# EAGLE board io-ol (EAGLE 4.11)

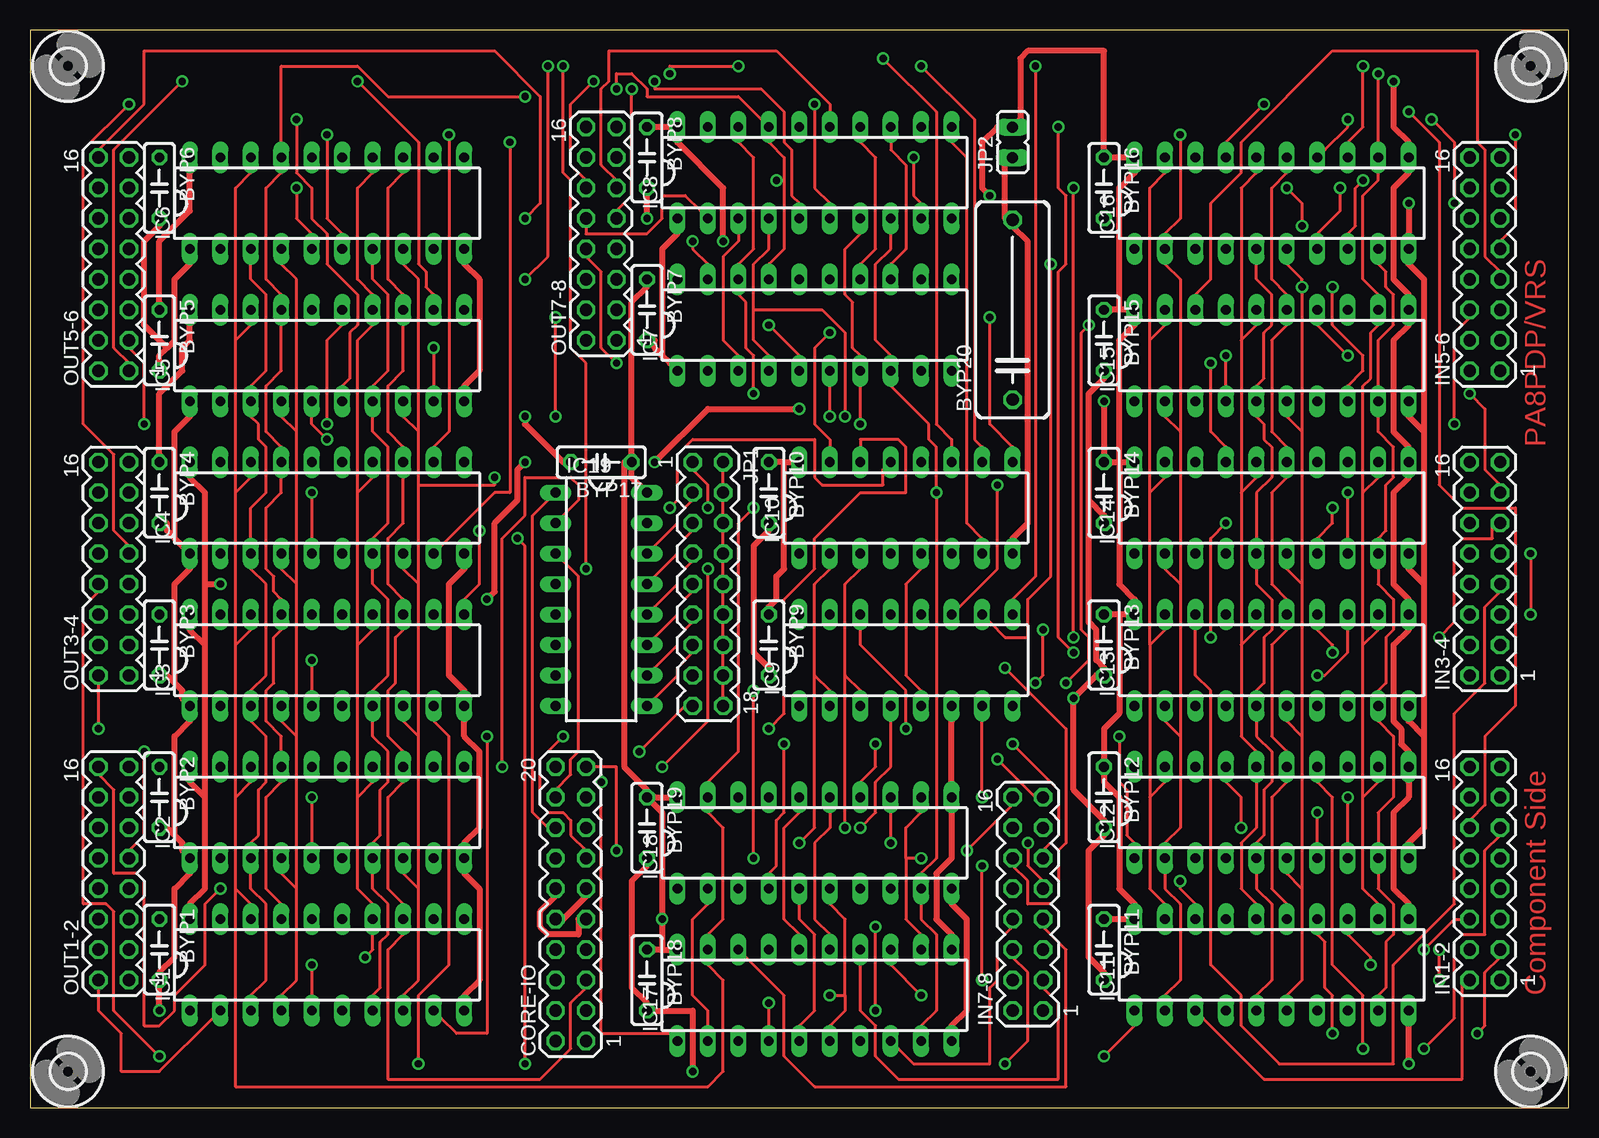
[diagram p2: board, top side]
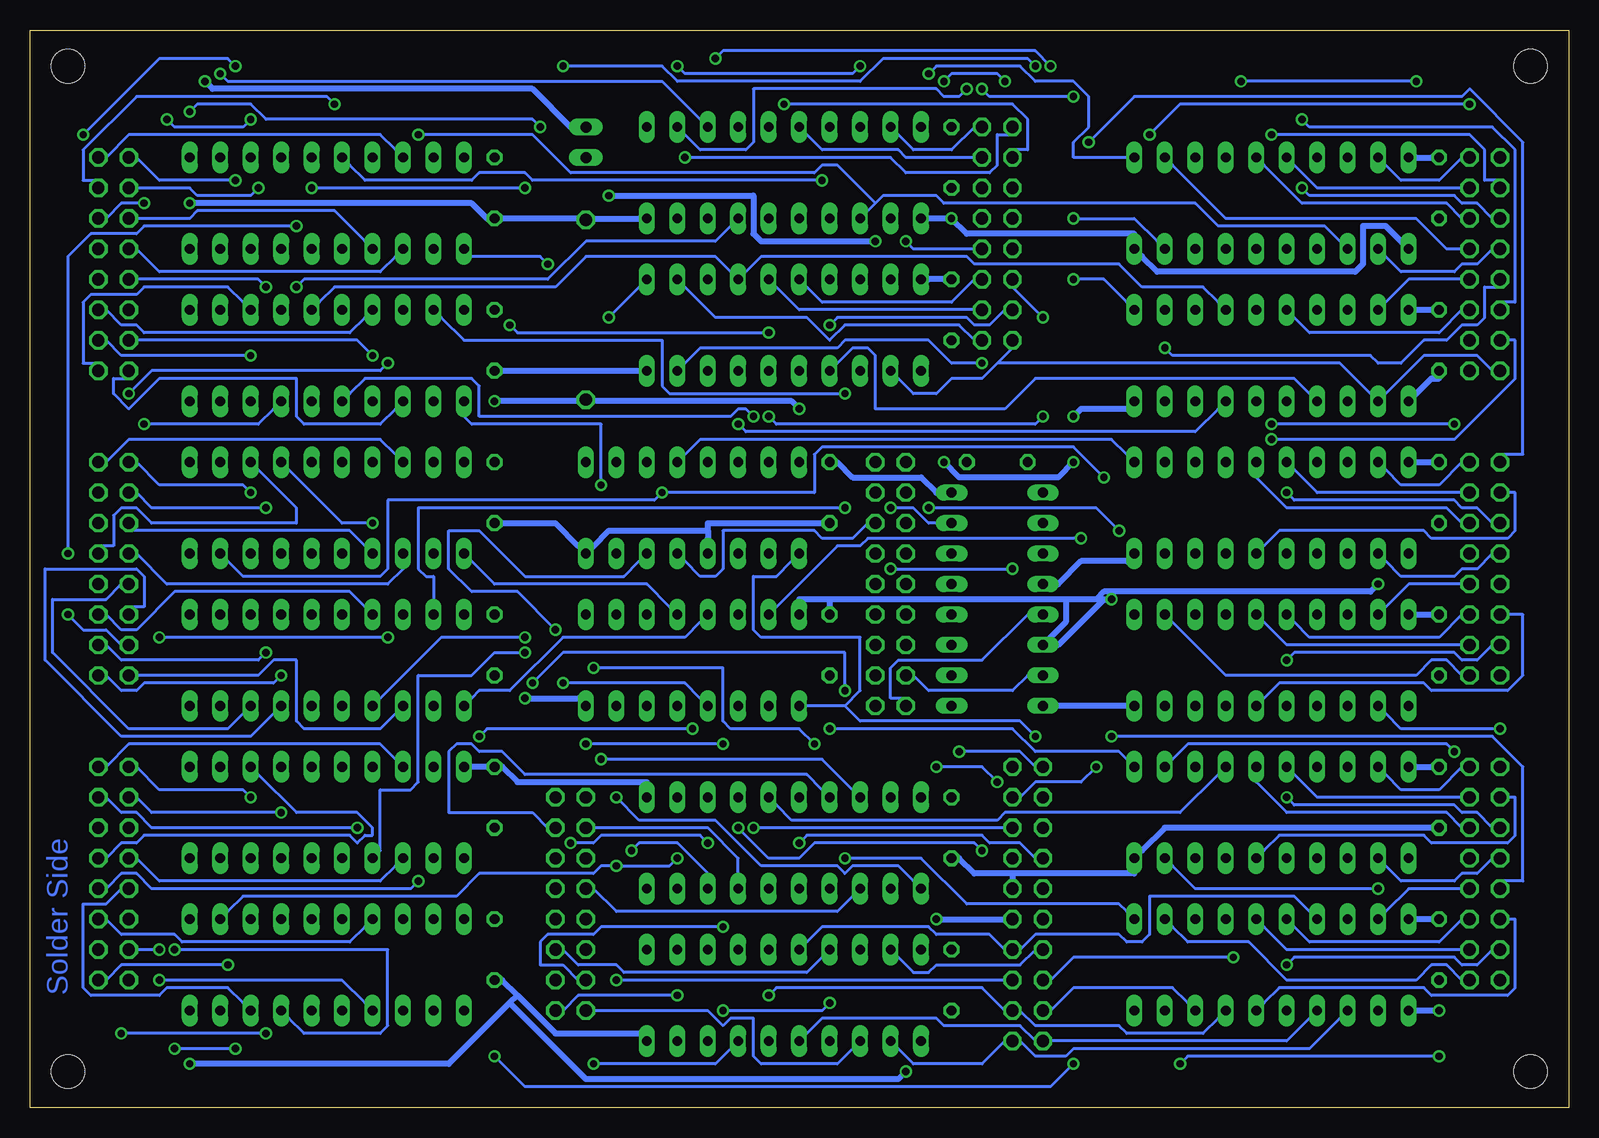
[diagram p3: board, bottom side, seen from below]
Size 128.25 x 89.84 mm. Coordinates in mm from the lower left corner, seen from the top.
Outline: 0,0 128.25,0 128.25,89.84 0,89.84 0,0
Copper layers (1*16): Top 0.035mm / dielectric 1.5mm / Bottom 0.035mm
Design rules "olimex10mil": minimum track width 10mil, minimum drill 24mil, track to track 10mil, track to pad 10mil, pad to pad 10mil, via to via 10mil, smd to smd 10mil, copper to edge 40mil, drill to drill 10mil, minimum pad ring 10mil, minimum via ring 8mil, stop-mask expansion 0mil, vias tented up to drill 0mil, thermal gap 10mil
Net classes: 1 Power: width 0.508 mm, drill 0.254 mm, clearance 0.254 mm

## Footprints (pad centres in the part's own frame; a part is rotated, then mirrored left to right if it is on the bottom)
C050-025X075 = drill 0.813 octagon: 1 -2.54,0; 2 2.54,0
C150-064X183 = drill 1.016 octagon: 1 -7.493,0; 2 7.493,0
MA10-2 = drill 1.016 octagon: 1 -11.43,-1.27; 2 -11.43,1.27; 3 -8.89,-1.27; 4 -8.89,1.27; 5 -6.35,-1.27; 6 -6.35,1.27; 7 -3.81,-1.27; 8 -3.81,1.27; 9 -1.27,-1.27; 10 -1.27,1.27; 11 1.27,-1.27; 12 1.27,1.27; 13 3.81,-1.27; 14 3.81,1.27; 15 6.35,-1.27; 16 6.35,1.27; 17 8.89,-1.27; 18 8.89,1.27; 19 11.43,-1.27; 20 11.43,1.27
DIL20 = drill 0.813 long: 1 -11.43,-3.81; 2 -8.89,-3.81; 3 -6.35,-3.81; 4 -3.81,-3.81; 5 -1.27,-3.81; 6 1.27,-3.81; 7 3.81,-3.81; 8 6.35,-3.81; 9 8.89,-3.81; 10 11.43,-3.81; 11 11.43,3.81; 12 8.89,3.81; 13 6.35,3.81; 14 3.81,3.81; 15 1.27,3.81; 16 -1.27,3.81; 17 -3.81,3.81; 18 -6.35,3.81; 19 -8.89,3.81; 20 -11.43,3.81
DIL16 = drill 0.813 long: 1 -8.89,-3.81; 2 -6.35,-3.81; 3 -3.81,-3.81; 4 -1.27,-3.81; 5 1.27,-3.81; 6 3.81,-3.81; 7 6.35,-3.81; 8 8.89,-3.81; 9 8.89,3.81; 10 6.35,3.81; 11 3.81,3.81; 12 1.27,3.81; 13 -1.27,3.81; 14 -3.81,3.81; 15 -6.35,3.81; 16 -8.89,3.81
MA08-2 = drill 1.016 octagon: 1 -8.89,-1.27; 2 -8.89,1.27; 3 -6.35,-1.27; 4 -6.35,1.27; 5 -3.81,-1.27; 6 -3.81,1.27; 7 -1.27,-1.27; 8 -1.27,1.27; 9 1.27,-1.27; 10 1.27,1.27; 11 3.81,-1.27; 12 3.81,1.27; 13 6.35,-1.27; 14 6.35,1.27; 15 8.89,-1.27; 16 8.89,1.27
MA09-2 = drill 1.016 octagon: 1 -10.16,-1.27; 2 -10.16,1.27; 3 -7.62,-1.27; 4 -7.62,1.27; 5 -5.08,-1.27; 6 -5.08,1.27; 7 -2.54,-1.27; 8 -2.54,1.27; 9 0,-1.27; 10 0,1.27; 11 2.54,-1.27; 12 2.54,1.27; 13 5.08,-1.27; 14 5.08,1.27; 15 7.62,-1.27; 16 7.62,1.27; 17 10.16,-1.27; 18 10.16,1.27
JP1 = drill 0.914 long: 1 0,-1.27; 2 0,1.27
2,8 = hole 2.8: 0,0

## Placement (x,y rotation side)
BYP1  .01uf  [C050-025X075]  10.79,13.17 270 top
BYP2  .01uf  [C050-025X075]  10.79,25.87 270 top
BYP3  .01uf  [C050-025X075]  10.79,38.57 270 top
BYP4  .01uf  [C050-025X075]  10.79,51.27 270 top
BYP5  .01uf  [C050-025X075]  10.79,63.97 270 top
BYP6  .01uf  [C050-025X075]  10.79,76.67 270 top
BYP7  .01uf  [C050-025X075]  51.43,66.51 270 top
BYP8  .01uf  [C050-025X075]  51.43,79.21 270 top
BYP9  .01uf  [C050-025X075]  61.59,38.57 270 top
BYP10  .01uf  [C050-025X075]  61.59,51.27 270 top
BYP11  .01uf  [C050-025X075]  89.53,13.17 270 top
BYP12  .01uf  [C050-025X075]  89.53,25.87 270 top
BYP13  .01uf  [C050-025X075]  89.53,38.57 270 top
BYP14  .01uf  [C050-025X075]  89.53,51.27 270 top
BYP15  .01uf  [C050-025X075]  89.53,63.97 270 top
BYP16  .01uf  [C050-025X075]  89.53,76.67 270 top
BYP17  .01uf  [C050-025X075]  47.62,53.81 180 top
BYP18  .01uf  [C050-025X075]  51.43,10.63 270 top
BYP19  .01uf  [C050-025X075]  51.43,23.33 270 top
BYP20  100uf 25V  [C150-064X183]  81.91,66.51 90 top
CORE-IO  CORE-IO  [MA10-2]  45.08,16.98 90 top
IC1  74LS374N  [DIL20]  24.76,11.9 0 top
IC2  74LS374N  [DIL20]  24.76,24.6 0 top
IC3  74LS374N  [DIL20]  24.76,37.3 0 top
IC4  74LS374N  [DIL20]  24.76,50 0 top
IC5  74LS374N  [DIL20]  24.76,62.7 0 top
IC6  74LS374N  [DIL20]  24.76,75.4 0 top
IC7  74LS374N  [DIL20]  65.4,65.24 0 top
IC8  74LS374N  [DIL20]  65.4,77.94 0 top
IC9  74LS138N  [DIL16]  73.02,37.3 0 top
IC10  74LS138N  [DIL16]  73.02,50 0 top
IC11  74LS373N  [DIL20]  103.5,11.9 0 top
IC12  74LS373N  [DIL20]  103.5,24.6 0 top
IC13  74LS373N  [DIL20]  103.5,37.3 0 top
IC14  74LS373N  [DIL20]  103.5,50 0 top
IC15  74LS373N  [DIL20]  103.5,62.7 0 top
IC16  74LS373N  [DIL20]  103.5,75.4 0 top
IC17  74LS373N  [DIL20]  65.4,9.36 0 top
IC18  74LS373N  [DIL20]  65.4,22.06 0 top
IC19  74LS138N  [DIL16]  47.62,42.38 270 top
IN1-2  [MA08-2]  121.28,19.52 90 top
IN3-4  [MA08-2]  121.28,44.92 90 top
IN5-6  [MA08-2]  121.28,70.32 90 top
IN7-8  [MA08-2]  83.18,16.98 90 top
JP1  DEVSEL  [MA09-2]  56.51,43.65 270 top
JP2  POWER  [JP1]  81.91,80.48 0 top
OUT1-2  [MA08-2]  6.98,19.52 90 top
OUT3-4  [MA08-2]  6.98,44.92 90 top
OUT5-6  [MA08-2]  6.98,70.32 90 top
OUT7-8  [MA08-2]  47.62,72.86 90 top
U$1  [2,8]  125.09,3.01 0 top
U$2  [2,8]  125.09,86.83 0 top
U$3  [2,8]  3.17,86.83 0 top
U$4  [2,8]  3.17,3.01 0 top

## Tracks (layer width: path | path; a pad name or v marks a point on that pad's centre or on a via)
GND  (via drill 0.61)
  Top 0.508: IC1.10 36.19,9.36 37.46,10.63 37.46,18.25 36.19,19.52 IC2.10 36.19,22.06 37.46,23.33 37.46,29.68 36.19,30.95 36.19,32.22 IC3.10 36.19,34.76 34.92,36.03 34.92,43.65 36.19,44.92 IC4.10 | 52.7,62.7 52.07,63.34 52.07,63.97 BYP7.2 | 52.7,62.7 53.34,62.06 IC7.1 | 52.7,62.7 52.7,71.59 53.97,72.86 IC8.1 | v51.43,74.13 51.43,76.03 BYP8.2 | IC5.10 36.19,60.16 37.46,61.43 37.46,69.05 36.19,70.32 IC6.10 | v41.27,57.62 41.27,56.98 44.45,53.81 BYP17.2 | 11.43,63.34 10.79,62.7 10.79,62.06 BYP5.2 | 11.43,63.34 12.06,63.97 12.06,69.05 13.33,70.32 IC6.1 | 11.43,63.34 9.52,65.24 9.52,72.22 10.79,73.5 BYP6.2 | 12.06,47.46 11.43,48.09 11.43,48.73 BYP4.2 | 12.06,47.46 12.7,46.82 IC4.1 13.33,44.92 12.06,43.65 12.06,35.39 | 12.06,35.39 12.7,34.76 12.7,34.12 IC3.1 13.33,32.22 12.06,30.95 12.06,22.7 | 12.06,35.39 11.43,36.03 BYP3.2 | 12.06,22.7 12.7,22.06 12.7,21.42 IC2.1 13.33,19.52 12.06,18.25 12.06,12.54 10.79,11.27 BYP1.2 10.79,10 v10.79,8.09 | 12.06,22.7 11.43,23.33 BYP2.2 | 12.06,47.46 12.06,56.35 13.33,57.62 IC5.1 | IC17.10 76.83,6.82 78.1,8.09 78.1,15.71 76.83,16.98 IC18.10 | v114.93,3.64 114.93,6.82 IC11.10 | BYP11.2 89.53,11.27 88.26,12.54 88.26,21.42 89.53,22.7 BYP12.2 89.53,23.96 86.99,26.5 v86.99,34.12 88.89,36.03 BYP13.2 89.53,36.66 88.89,37.3 88.89,39.84 88.26,40.48 88.26,50.63 | 116.2,30.95 116.2,23.33 114.93,22.06 IC12.10 | 116.2,30.95 114.93,32.22 IC13.10 | 116.2,43.65 114.93,44.92 IC14.10 | 116.2,43.65 116.2,30.95 | 116.2,56.35 114.93,57.62 IC15.10 | 116.2,56.35 116.2,43.65 | 116.2,56.35 116.2,69.05 114.93,70.32 IC16.10 114.93,72.86 v114.93,75.4 | JP2.1 81.27,78.58 81.27,74.13 BYP20.2 81.91,73.5 83.18,72.22 83.18,48.73 81.91,47.46 IC10.8
  Top 0.508: BYP9.2 61.59,36.66 60.32,37.94 60.32,46.82 61.59,48.09 BYP10.2 | 88.26,50.63 88.26,59.52 89.53,60.8 BYP15.2 | 88.26,50.63 89.53,49.37 BYP14.2 | v55.24,3.01 55.24,8.09 52.07,8.09 BYP18.2 51.43,8.73 50.16,10 50.16,18.88 51.43,20.15 BYP19.2 | CORE-IO.10 44.45,15.71 46.35,17.61 CORE-IO.11
  Bottom 0.508: IC3.10 36.83,33.49 42.54,33.49 IC19.8 | IC19.4 42.54,43.65 40.64,45.55 36.83,45.55 IC4.10 | 46.35,19.52 36.19,19.52 IC2.10 35.55,21.42 33.65,23.33 11.43,23.33 BYP2.2 | 46.35,19.52 49.53,19.52 50.8,20.79 BYP19.2 | IC8.1 53.34,74.13 v51.43,74.13 50.16,72.86 36.19,72.86 IC6.10 35.55,70.95 34.29,69.69 17.77,69.69 17.14,70.32 17.14,73.5 15.24,73.5 13.97,72.22 IC6.1 | v41.27,57.62 40.64,58.25 36.83,58.25 IC5.10 | IC5.1 12.7,59.52 11.43,60.8 10.79,60.8 BYP5.2 | v10.79,8.09 12.7,8.09 IC1.1 | v86.99,34.12 82.55,34.12 IC9.8 | 87.62,9.36 84.45,6.18 77.46,6.18 IC17.10 | 87.62,9.36 88.89,10.63 BYP11.2 | v114.93,3.64 93.34,3.64 88.26,8.73 | 88.26,8.73 87.62,9.36 | IC8.10 77.46,74.13 81.27,74.13 BYP20.2 82.55,74.13 88.89,74.13 BYP16.2 90.16,74.13 91.44,75.4 v114.93,75.4 | IC7.10 77.46,61.43 88.89,61.43 BYP15.2 | BYP14.2 88.89,48.73 84.45,48.73 82.55,46.82 IC10.8 81.27,46.82 80,48.09 71.75,48.09 | 71.75,48.09 71.75,48.73 62.23,48.73 BYP10.2 | 71.75,48.09 71.75,47.46 IC10.4 | v55.24,3.01 55.88,2.38 81.91,2.38 88.26,8.73 | 46.35,19.52 46.35,18.88 CORE-IO.11
IN00  (via drill 0.61)
  Top 0.254: v40.64,47.46 41.27,46.82 v41.27,3.64 | v89.53,4.28 92.07,6.82 IC11.1
  Bottom 0.254: v40.64,47.46 58.41,47.46 59.05,46.82 60.96,46.82 66.03,41.74 IC9.15 | v41.27,3.64 43.18,1.74 86.99,1.74 v89.53,4.28
IN01  (via drill 0.61)
  Top 0.254: v90.8,30.95 90.8,27.14 91.44,26.5 91.44,22.7 92.07,22.06 IC12.1 | v73.02,31.58 73.02,34.76 69.21,38.57 69.21,39.84 IC9.14
  Bottom 0.254: v90.8,30.95 90.16,31.58 v73.02,31.58
IN02
  Bottom 0.254: IC13.1 91.44,34.12 90.8,34.76 88.26,34.76 83.81,39.2 73.66,39.2 72.38,40.48 IC9.13
IN03
  Bottom 0.254: IC9.12 74.92,41.74 76.83,43.65 89.53,43.65 91.44,45.55 IC14.1
IN04  (via drill 0.61)
  Top 0.254: v80.64,51.91 80.64,44.92 77.46,41.74 IC9.11
  Bottom 0.254: v80.64,51.91 80.64,56.98 91.44,56.98 92.07,57.62 IC15.1
IN05  (via drill 0.61)
  Top 0.254: v85.08,70.32 85.08,44.28 83.18,42.38 83.18,39.2 81.27,39.2 80,40.48 IC9.10
  Bottom 0.254: v85.08,70.32 85.72,70.95 91.44,70.95 IC16.1
IN06  (via drill 0.61)
  Top 0.254: v47.62,27.14 47.62,6.18 53.34,6.18 IC17.1 | v52.7,28.41 56.51,32.22 v56.51,44.92 | v46.35,44.92 46.35,62.06 45.08,63.34 45.08,77.3 44.45,77.94 v44.45,86.83 | v83.81,86.83 83.81,44.28 81.91,42.38 IC9.9
  Bottom 0.254: v47.62,27.14 48.89,28.41 v52.7,28.41 | v56.51,44.92 v46.35,44.92 | v44.45,86.83 45.08,87.47 57.15,87.47 59.05,85.56 74.29,85.56 75.56,86.83 v83.81,86.83
IN07  (via drill 0.61)
  Top 0.254: v79.37,25.87 79.37,32.22 IC9.7
  Bottom 0.254: v79.37,25.87 77.46,23.96 71.11,23.96 67.3,20.15 60.96,20.15 60.32,19.52 59.69,20.15 55.88,20.15 54.61,18.88 IC18.1
N$1
  Bottom 0.254: IC12.3 97.78,20.15 99.05,18.88 117.47,18.88 119.38,20.79 IN1-2.10
N$2  (via drill 0.61)
  Top 0.254: v86.99,37.94 85.72,39.2 85.72,69.69 86.35,70.32 86.35,76.03 85.72,76.67 v85.72,81.75 | v114.93,83.02 117.47,80.48 117.47,51.91 119.38,50 123.82,50 123.82,33.49 121.28,30.95 121.28,25.23 120.01,23.96 IN1-2.12
  Bottom 0.254: v86.99,37.94 89.53,37.94 91.44,36.03 95.88,36.03 95.88,27.14 96.52,26.5 99.05,26.5 99.05,21.42 IC12.4 | v85.72,81.75 86.35,82.39 108.58,82.39 109.85,83.66 114.3,83.66 v114.93,83.02
N$3  (via drill 0.61)
  Top 0.254: v56.51,50 56.51,51.91 55.24,53.17 JP1.1
  Bottom 0.254: v56.51,50 54.61,50 53.34,48.73 52.7,48.73 IC19.15
N$4
  Top 0.254: IC19.14 52.07,46.82 53.97,48.73 53.97,49.37 55.24,50.63 JP1.3
N$5
  Top 0.254: IC19.13 52.07,44.28 53.97,46.19 53.97,46.82 55.24,48.09 JP1.5
N$6
  Top 0.254: IC19.12 52.07,41.74 53.97,43.65 53.97,44.28 55.24,45.55 JP1.7
N$7  (via drill 0.61)
  Top 0.254: v107.31,24.6 107.31,22.06 IC12.7
  Bottom 0.254: v107.31,24.6 118.1,24.6 119.38,25.87 IN1-2.14
N$8  (via drill 0.61)
  Top 0.254: v109.85,25.87 109.85,22.06 IC12.8
  Bottom 0.254: v109.85,25.87 110.48,26.5 117.47,26.5 119.38,28.41 IN1-2.16
N$9
  Bottom 0.254: IC11.8 110.48,8.73 111.75,10 116.83,10 117.47,9.36 123.19,9.36 123.82,10 123.82,16.98 121.91,16.98 120.64,18.25 IN1-2.8
N$10  (via drill 0.61)
  Top 0.254: v116.2,13.17 118.74,15.71 119.38,15.71 IN1-2.6
  Bottom 0.254: v116.2,13.17 98.42,13.17 98.42,6.82 99.05,6.18 105.41,6.18 106.67,7.46 IC11.7
N$11  (via drill 0.61)
  Top 0.254: v117.47,10.63 v117.47,13.17
  Bottom 0.254: v117.47,10.63 102.23,10.63 100.32,8.73 IC11.4 | v117.47,13.17 119.38,13.17 IN1-2.4
N$12
  Top 0.254: IC11.3 97.78,7.46 102.86,2.38 119.38,2.38 119.38,10.63 IN1-2.2
N$13  (via drill 0.61)
  Top 0.254: v111.75,11.9 111.75,12.54 109.85,14.44 IC11.13
  Bottom 0.254: v111.75,11.9 120.64,11.9 121.91,10.63 IN1-2.1
N$14  (via drill 0.61)
  Top 0.254: v108.58,6.18 108.58,9.36 107.94,10 107.94,13.81 107.31,14.44 IC11.14 | v120.64,6.18 121.28,6.82 121.28,11.27 122.55,12.54 IN1-2.3
  Bottom 0.254: v108.58,6.18 v120.64,6.18
N$15
  Bottom 0.254: IC11.17 100.32,15.08 101.59,13.81 115.56,13.81 116.2,14.44 120.64,14.44 121.91,15.71 IN1-2.5
N$16  (via drill 0.61)
  Top 0.254: v95.88,18.88 95.88,18.25 97.15,16.98 IC11.18
  Bottom 0.254: v95.88,18.88 96.52,18.25 118.1,18.25 119.38,19.52 120.64,19.52 121.91,18.25 IN1-2.7
N$17
  Bottom 0.254: IC12.13 109.21,27.77 106.04,24.6 100.96,24.6 99.69,23.33 99.69,22.7 100.32,22.7 100.96,22.06 101.59,22.7 118.74,22.7 119.38,22.06 120.64,22.06 121.91,20.79 IN1-2.9
N$18  (via drill 0.61)
  Top 0.254: v111.12,4.92 111.12,9.36 108.58,11.9 108.58,25.87 107.31,27.14 IC12.14 | v116.2,4.92 118.74,7.46 118.74,13.81 119.38,14.44 121.28,14.44 121.28,21.42 122.55,22.7 IN1-2.11
  Bottom 0.254: v111.12,4.92 v116.2,4.92
N$19  (via drill 0.61)
  Top 0.254: v100.96,23.33 100.96,25.87 99.69,27.14 IC12.17
  Bottom 0.254: v100.96,23.33 118.1,23.33 119.38,24.6 120.64,24.6 121.91,25.87 IN1-2.13
N$20
  Bottom 0.254: IC12.18 97.78,29.04 99.05,30.31 120.01,30.31 121.91,28.41 IN1-2.15
N$21
  Top 0.254: IC19.11 52.07,39.2 53.97,41.11 53.97,41.74 55.24,43.02 JP1.9
N$22
  Top 0.254: IC19.10 52.07,36.66 53.97,38.57 53.97,39.2 55.24,40.48 JP1.11
N$23
  Top 0.254: IC19.9 52.07,34.12 53.97,36.03 53.97,36.66 55.24,37.94 JP1.13
N$24
  Bottom 0.254: IC19.7 45.08,36.03 46.35,34.76 53.34,34.76 54.61,36.03 JP1.15
N$25
  Top 0.254: IC9.5 74.29,34.76 73.02,36.03 73.02,43.65 74.29,44.92 IC10.5 | JP1.18 57.78,34.12 57.78,35.39 JP1.16 57.78,36.66 57.78,37.94 JP1.14 57.78,39.2 57.78,40.48 JP1.12 57.78,41.74 57.78,43.02 JP1.10 57.78,44.28 57.78,45.55 JP1.8 57.78,46.82 57.78,48.09 JP1.6 57.78,49.37 57.78,50.63 JP1.4 57.78,51.91 57.78,53.17 JP1.2
  Bottom 0.254: IC10.5 73.66,45.55 72.38,44.28 71.11,44.28 70.48,44.92 70.48,48.09 62.86,48.09 62.23,47.46 59.69,47.46 58.41,48.73 JP1.6
N$26
  Bottom 0.254: OUT5-6.2 6.34,61.43 7.62,62.7 12.06,62.7 15.24,59.52 IC5.2 16.5,59.52 19.04,62.06 47.62,62.06 | 47.62,62.06 46.35,63.34 OUT7-8.2 | 47.62,62.06 48.89,60.8 51.43,60.8 52.7,59.52 54.61,59.52 55.88,60.8 IC7.2
N$27  (via drill 0.61)
  Top 0.254: v78.1,21.42 81.91,25.23 IN7-8.16
  Bottom 0.254: v78.1,21.42 77.46,22.06 74.29,22.06 71.75,19.52 IC18.8
N$28
  Bottom 0.254: IC18.3 59.69,17.61 60.96,16.34 79.37,16.34 81.27,18.25 IN7-8.10
N$29
  Bottom 0.254: IC14.3 97.15,44.92 98.42,43.65 116.83,43.65 119.38,46.19 IN3-4.10
N$30
  Bottom 0.254: IC14.4 100.32,46.82 101.59,48.09 120.01,48.09 IN3-4.12
N$31  (via drill 0.61)
  Top 0.254: v108.58,50 108.58,48.73 107.31,47.46 IC14.7
  Bottom 0.254: v108.58,50 118.1,50 119.38,51.27 IN3-4.14
N$32  (via drill 0.61)
  Top 0.254: v109.85,51.27 109.85,47.46 IC14.8
  Bottom 0.254: v109.85,51.27 110.48,51.91 117.47,51.91 119.38,53.81 IN3-4.16
N$33
  Bottom 0.254: IC3.12 33.02,40.48 28.57,36.03 12.7,36.03 11.43,37.3 10.16,37.3 8.89,36.03 OUT3-4.1
N$34
  Bottom 0.254: IC3.15 25.39,40.48 23.49,38.57 8.89,38.57 OUT3-4.3
N$35
  Bottom 0.254: IC3.16 22.86,40.48 21.58,39.2 10.79,39.2 8.89,41.11 OUT3-4.5
N$36
  Bottom 0.254: IC3.19 15.24,41.74 13.33,43.65 8.89,43.65 OUT3-4.7
N$37
  Bottom 0.254: IC13.3 97.78,32.85 99.05,31.58 105.41,31.58 106.04,32.22 106.04,37.3 107.94,37.3 109.21,36.03 119.38,36.03 IN3-4.2
N$38  (via drill 0.61)
  Top 0.254: v86.99,39.2 v86.99,76.67 | v104.77,76.67 106.04,75.4 v106.04,73.5 | v125.09,46.19 v125.09,41.11
  Bottom 0.254: v86.99,39.2 93.97,39.2 99.05,34.12 IC13.4 | v86.99,76.67 v104.77,76.67 | v106.04,73.5 118.74,73.5 119.38,72.86 123.19,72.86 125.09,70.95 v125.09,46.19 | v125.09,41.11 123.82,39.84 121.91,39.84 120.64,38.57 IN3-4.4
N$39
  Bottom 0.254: IC13.7 107.94,32.85 109.85,30.95 120.64,30.95 126.99,37.3 126.99,44.92 119.38,44.92 118.74,44.28 118.74,41.74 120.01,41.74 IN3-4.6
N$40
  Bottom 0.254: IC13.8 110.48,32.85 111.75,31.58 120.01,31.58 126.36,37.94 126.36,42.38 121.91,42.38 120.64,43.65 IN3-4.8
N$41
  Bottom 0.254: IC14.13 109.21,53.17 106.04,50 106.04,48.73 118.1,48.73 119.38,50 120.64,50 121.28,49.37 121.28,46.82 122.55,46.82 IN3-4.9
N$42  (via drill 0.61)
  Top 0.254: v99.69,48.73 98.42,47.46 v98.42,39.2 | v117.47,39.2 118.74,40.48 118.74,46.82 119.38,47.46 121.91,47.46 121.91,48.73 IN3-4.11
  Bottom 0.254: v99.69,48.73 102.23,48.73 106.67,53.17 IC14.14 | v98.42,39.2 v117.47,39.2
N$43  (via drill 0.61)
  Top 0.254: v98.42,62.06 98.42,56.35 99.69,55.08 IC14.17 | v120.01,59.52 121.28,58.25 121.28,53.17 122.55,51.91 IN3-4.13
  Bottom 0.254: v98.42,62.06 99.05,61.43 118.1,61.43 v120.01,59.52
N$44
  Bottom 0.254: IC14.18 97.78,54.45 99.05,55.71 120.01,55.71 121.91,53.81 IN3-4.15
N$45  (via drill 0.61)
  Top 0.254: v107.31,36.03 107.94,36.03 109.85,37.94 109.85,39.84 IC13.13
  Bottom 0.254: v107.31,36.03 107.94,35.39 118.74,35.39 119.38,34.76 120.64,34.76 121.91,36.03 IN3-4.1
N$46  (via drill 0.61)
  Top 0.254: v108.58,37.94 108.58,38.57 107.31,39.84 IC13.14
  Bottom 0.254: v108.58,37.94 109.21,37.3 120.64,37.3 121.91,38.57 IN3-4.3
N$47
  Bottom 0.254: IC13.17 100.32,41.74 101.59,43.02 116.2,43.02 119.38,39.84 120.64,39.84 121.91,41.11 IN3-4.5
N$48
  Top 0.254: IC13.18 97.15,39.84 97.15,36.03 98.42,34.76 98.42,11.9 100.96,9.36 100.96,6.82 104.13,3.64 113.66,3.64 113.66,11.9 118.74,16.98 118.74,32.85 121.28,35.39 121.28,41.74 122.55,43.02 IN3-4.7
N$49  (via drill 0.61)
  Top 0.254: v23.49,37.3 23.49,34.76 IC3.5
  Bottom 0.254: v23.49,37.3 22.86,37.94 9.52,37.94 8.89,37.3 7.62,37.3 6.34,38.57 OUT3-4.4
N$50
  Bottom 0.254: IC3.6 25.39,34.12 24.12,35.39 12.06,35.39 11.43,34.76 5.08,34.76 3.8,36.03 3.8,41.11 5.08,41.11 OUT3-4.6
N$51  (via drill 0.61)
  Top 0.254: v5.71,31.58 5.71,35.39 OUT3-4.2
  Bottom 0.254: v5.71,31.58 13.97,31.58 15.24,32.85 IC3.2
N$52  (via drill 0.61)
  Top 0.254: v32.38,3.64 32.38,9.36 34.92,11.9 34.92,30.95 33.65,32.22 IC3.9 | v10.79,4.28 6.98,8.09 6.98,16.34 6.34,16.98 4.44,16.98 4.44,41.74 5.71,43.02 OUT3-4.8
  Bottom 0.254: v32.38,3.64 31.74,4.28 v10.79,4.28
N$53
  Bottom 0.254: IC1.12 33.02,15.08 31.74,13.81 26.66,13.81 23.49,10.63 12.7,10.63 11.43,11.9 10.16,11.9 8.89,10.63 OUT1-2.1
N$54
  Bottom 0.254: IC1.15 25.39,15.08 23.49,13.17 8.89,13.17 OUT1-2.3
N$55
  Bottom 0.254: IC1.16 22.86,15.08 21.58,13.81 10.79,13.81 8.89,15.71 OUT1-2.5
N$56
  Bottom 0.254: IC1.19 15.24,16.34 13.33,18.25 8.89,18.25 OUT1-2.7
N$57
  Top 0.254: IC1.2 15.24,7.46 10.79,3.01 7.62,3.01 7.62,6.18 5.71,8.09 5.71,10 OUT1-2.2
N$58  (via drill 0.61)
  Top 0.254: v23.49,11.9 23.49,9.36 IC1.5
  Bottom 0.254: v23.49,11.9 22.86,12.54 9.52,12.54 8.89,11.9 7.62,11.9 6.34,13.17 OUT1-2.4
N$59
  Bottom 0.254: IC1.6 25.39,8.73 24.12,10 12.06,10 11.43,9.36 5.08,9.36 4.44,10 4.44,15.71 5.08,15.71 OUT1-2.6
N$60  (via drill 0.61)
  Top 0.254: v38.1,30.95 38.1,6.18 35.55,6.18 34.29,7.46 IC1.9
  Bottom 0.254: v38.1,30.95 6.34,30.95 3.8,28.41 3.8,18.88 5.71,18.88 OUT1-2.8
N$61
  Bottom 0.254: IC2.19 15.24,27.77 13.97,26.5 10.79,26.5 8.89,28.41 OUT1-2.15
N$62
  Bottom 0.254: IC2.16 22.86,27.77 20.95,25.87 8.89,25.87 OUT1-2.13
N$63
  Bottom 0.254: IC2.15 26.03,27.14 23.49,24.6 10.16,24.6 8.89,23.33 OUT1-2.11
N$64  (via drill 0.61)
  Top 0.254: v9.52,29.68 9.52,22.7 8.25,21.42 OUT1-2.9
  Bottom 0.254: v9.52,29.68 10.16,30.31 31.74,30.31 33.02,29.04 IC2.12
N$65
  Bottom 0.254: IC2.2 15.24,20.15 13.97,18.88 9.52,18.88 8.89,19.52 7.62,19.52 6.34,20.79 OUT1-2.10
N$66  (via drill 0.61)
  Top 0.254: v23.49,25.87 23.49,22.06 IC2.5
  Bottom 0.254: v23.49,25.87 22.86,25.23 9.52,25.23 8.89,24.6 7.62,24.6 6.34,23.33 OUT1-2.12
N$67
  Bottom 0.254: IC2.6 25.39,21.42 24.12,22.7 12.06,22.7 11.43,22.06 5.08,22.06 4.44,22.7 4.44,25.87 5.08,25.87 OUT1-2.14
N$68  (via drill 0.61)
  Top 0.254: v15.87,18.25 14.6,16.98 14.6,11.9 12.06,9.36 12.06,8.09 10.79,6.82 9.52,6.82 9.52,18.88 8.89,19.52 6.98,19.52 6.98,26.5 5.71,27.77 OUT1-2.16
  Bottom 0.254: v15.87,18.25 31.11,18.25 33.02,20.15 IC2.9
N$69
  Bottom 0.254: IC4.2 15.24,45.55 13.97,44.28 9.52,44.28 8.89,44.92 7.62,44.92 6.34,46.19 OUT3-4.10
N$70  (via drill 0.61)
  Top 0.254: v23.49,51.27 23.49,47.46 IC4.5
  Bottom 0.254: v23.49,51.27 22.86,50.63 9.52,50.63 8.89,50 7.62,50 6.34,48.73 OUT3-4.12
N$71
  Bottom 0.254: IC4.6 25.39,46.82 24.12,48.09 12.06,48.09 11.43,47.46 5.08,47.46 4.44,48.09 4.44,51.27 5.08,51.27 OUT3-4.14
N$72  (via drill 0.61)
  Top 0.254: v40,80.48 40,51.27 38.73,51.27 34.29,46.82 IC4.9
  Bottom 0.254: v40,80.48 36.19,84.29 8.89,84.29 8.25,84.92 3.8,80.48 3.8,54.45 5.71,54.45 OUT3-4.16
N$73
  Bottom 0.254: IC4.19 15.24,53.17 13.97,51.91 10.79,51.91 8.89,53.81 OUT3-4.15
N$74
  Bottom 0.254: IC4.16 22.86,53.17 20.95,51.27 8.89,51.27 OUT3-4.13
N$75
  Bottom 0.254: IC4.15 26.03,52.54 23.49,50 10.16,50 8.89,48.73 OUT3-4.11
N$76  (via drill 0.61)
  Top 0.254: v34.92,81.11 34.92,56.35 33.65,55.08 IC4.12 | v8.25,83.66 4.44,79.84 4.44,56.98 6.98,54.45 6.98,48.09 8.25,46.82 OUT3-4.9
  Bottom 0.254: v34.92,81.11 32.38,83.66 v8.25,83.66
N$77
  Bottom 0.254: IC16.3 97.78,70.95 99.05,69.69 117.47,69.69 119.38,71.59 IN5-6.10
N$78
  Bottom 0.254: IC16.4 100.32,72.22 102.86,74.77 114.3,74.77 114.93,74.13 119.38,74.13 IN5-6.12
N$79  (via drill 0.61)
  Top 0.254: v109.21,76.67 109.21,74.77 107.31,72.86 IC16.7
  Bottom 0.254: v109.21,76.67 109.85,76.03 114.3,76.03 114.93,76.67 119.38,76.67 IN5-6.14
N$80  (via drill 0.61)
  Top 0.254: v111.12,77.3 110.48,76.67 110.48,73.5 109.85,72.86 IC16.8
  Bottom 0.254: v111.12,77.3 117.47,77.3 119.38,79.21 IN5-6.16
N$81  (via drill 0.61)
  Top 0.254: v27.3,85.56 32.38,80.48 32.38,70.32 33.02,69.69 33.02,68.41 33.65,67.78 IC5.12 | v12.7,85.56 6.98,79.84 6.98,63.34 8.25,62.06 OUT5-6.1
  Bottom 0.254: v12.7,85.56 v27.3,85.56
N$82  (via drill 0.61)
  Top 0.254: v24.76,56.98 24.76,63.97 26.03,65.24 IC5.15 | v9.52,56.98 9.52,62.06 8.25,63.34 OUT5-6.3
  Bottom 0.254: v9.52,56.98 v24.76,56.98
N$83
  Bottom 0.254: IC5.16 22.86,65.88 21.58,64.61 10.79,64.61 8.89,66.51 OUT5-6.5
N$84
  Bottom 0.254: IC5.19 15.24,67.14 13.33,69.05 8.89,69.05 OUT5-6.7
N$85
  Bottom 0.254: IC7.12 73.66,68.41 71.11,65.88 63.5,65.88 61.59,63.97 60.32,65.24 50.8,65.24 49.53,63.97 OUT7-8.1
N$86
  Bottom 0.254: IC7.15 66.03,68.41 64.13,66.51 49.53,66.51 OUT7-8.3
N$87
  Bottom 0.254: IC7.16 63.5,68.41 62.23,67.14 51.43,67.14 49.53,69.05 OUT7-8.5
N$88  (via drill 0.61)
  Top 0.254: v55.24,72.22 55.24,71.59 56.51,70.32 IC7.19
  Bottom 0.254: v55.24,72.22 54.61,71.59 49.53,71.59 OUT7-8.7
N$89  (via drill 0.61)
  Top 0.254: v24.76,55.71 23.49,56.98 23.49,57.62 IC5.5
  Bottom 0.254: v24.76,55.71 9.52,55.71 4.44,60.8 4.44,63.97 5.08,63.97 OUT5-6.4
N$90  (via drill 0.61)
  Top 0.254: v22.22,82.39 22.22,77.94 23.49,76.67 23.49,74.13 24.76,72.86 24.76,70.32 27.3,67.78 27.3,65.24 26.66,64.61 26.66,60.8 26.03,60.16 IC5.6
  Bottom 0.254: v22.22,82.39 21.58,81.75 6.34,81.75 4.44,79.84 4.44,67.14 5.71,67.14 OUT5-6.6
N$91  (via drill 0.61)
  Top 0.254: v33.65,63.34 33.65,60.16 IC5.9
  Bottom 0.254: v33.65,63.34 33.02,62.7 16.5,62.7 15.87,62.06 13.97,62.06 12.06,63.97 10.16,63.97 8.89,65.24 7.62,65.24 6.98,65.88 6.98,68.41 5.71,68.41 OUT5-6.8
N$92
  Bottom 0.254: IC6.12 33.02,78.58 28.57,74.13 12.7,74.13 10.16,71.59 8.89,71.59 OUT5-6.9
N$93
  Bottom 0.254: IC6.15 25.39,78.58 22.22,75.4 10.16,75.4 8.89,74.13 OUT5-6.11
N$94  (via drill 0.61)
  Top 0.254: v62.86,30.31 62.86,24.6 62.23,23.96 62.23,20.15 61.59,19.52 IC18.4 | v81.27,36.66 86.35,31.58 86.35,22.06 85.72,21.42 85.72,17.61 85.08,16.98 83.18,16.98 83.18,18.88 81.91,20.15 IN7-8.12
  Bottom 0.254: v62.86,30.31 64.13,31.58 69.84,31.58 70.48,32.22 70.48,36.66 v81.27,36.66
N$95
  Bottom 0.254: IC6.16 22.86,78.58 20.95,76.67 8.89,76.67 OUT5-6.13
N$96
  Bottom 0.254: IC6.19 15.24,78.58 13.97,77.3 10.79,77.3 8.89,79.21 OUT5-6.15
N$97
  Bottom 0.254: IC6.2 15.24,70.95 13.97,69.69 9.52,69.69 8.89,70.32 7.62,70.32 6.34,71.59 OUT5-6.10
N$98  (via drill 0.61)
  Top 0.254: v22.22,76.67 22.22,74.13 23.49,72.86 IC6.5
  Bottom 0.254: v22.22,76.67 21.58,76.03 9.52,76.03 8.89,75.4 7.62,75.4 6.34,74.13 OUT5-6.12
N$99  (via drill 0.61)
  Top 0.254: v24.76,81.11 24.76,74.13 26.03,72.86 IC6.6
  Bottom 0.254: v24.76,81.11 8.25,81.11 6.98,79.84 6.98,77.3 5.71,77.3 OUT5-6.14
N$100  (via drill 0.61)
  Top 0.254: v41.27,74.13 42.54,75.4 42.54,84.29 38.73,88.1 9.52,88.1 9.52,83.66 5.71,79.84 OUT5-6.16
  Bottom 0.254: v41.27,74.13 36.19,74.13 34.29,72.22 IC6.9
N$101
  Bottom 0.254: IC15.3 97.78,58.25 99.05,56.98 105.41,56.98 106.04,57.62 106.04,60.8 117.47,60.8 120.01,58.25 121.28,59.52 121.28,60.8 120.01,60.8 IN5-6.2
N$102  (via drill 0.61)
  Top 0.254: v99.69,62.7 99.69,60.16 IC15.4
  Bottom 0.254: v99.69,62.7 100.96,63.97 119.38,63.97 IN5-6.4
N$103  (via drill 0.61)
  Top 0.254: v118.74,56.98 118.74,64.61 120.01,65.88 IN5-6.6
  Bottom 0.254: v118.74,56.98 109.21,56.98 107.94,58.25 IC15.7
N$104  (via drill 0.61)
  Top 0.254: v108.58,68.41 108.58,65.24 111.12,62.7 111.12,61.43 109.85,60.16 IC15.8
  Bottom 0.254: v108.58,68.41 109.21,69.05 119.38,69.05 IN5-6.8
N$105  (via drill 0.61)
  Top 0.254: v111.12,86.83 111.12,81.75 109.85,80.48 IC16.13 | v123.82,81.11 123.82,73.5 122.55,72.22 IN5-6.9
  Bottom 0.254: v111.12,86.83 111.75,87.47 117.47,87.47 v123.82,81.11
N$106  (via drill 0.61)
  Top 0.254: v109.85,82.39 109.85,81.75 107.94,79.84 IC16.14 | v116.83,82.39 118.74,80.48 v118.74,75.4
  Bottom 0.254: v109.85,82.39 110.48,81.75 116.2,81.75 v116.83,82.39 | v118.74,75.4 120.64,75.4 121.91,74.13 IN5-6.11
N$107  (via drill 0.61)
  Top 0.254: v102.86,83.66 99.69,80.48 IC16.17
  Bottom 0.254: v102.86,83.66 103.5,84.29 119.38,84.29 123.82,79.84 123.82,77.3 122.55,77.3 IN5-6.13
N$108
  Bottom 0.254: IC16.18 97.78,79.84 99.05,81.11 120.01,81.11 121.91,79.21 IN5-6.15
N$109
  Bottom 0.254: IC15.13 110.48,67.14 111.75,68.41 118.74,68.41 119.38,67.78 123.19,67.78 123.82,67.14 123.82,62.06 122.55,62.06 IN5-6.1
N$110  (via drill 0.61)
  Top 0.254: v109.85,62.7 107.31,65.24 IC15.14
  Bottom 0.254: v109.85,62.7 120.64,62.7 121.91,63.97 IN5-6.3
N$111
  Bottom 0.254: IC15.17 100.32,65.88 101.59,64.61 118.74,64.61 119.38,65.24 120.64,65.24 121.91,66.51 IN5-6.5
N$112
  Top 0.254: IC15.18 97.15,67.78 98.42,69.05 98.42,75.4 100.96,77.94 100.96,80.48 108.58,88.1 120.64,88.1 120.64,80.48 121.28,79.84 121.28,70.95 122.55,69.69 IN5-6.7
N$113
  Bottom 0.254: IC8.19 55.88,81.11 54.61,79.84 51.43,79.84 49.53,81.75 OUT7-8.15
N$114
  Bottom 0.254: IC8.16 63.5,81.11 62.23,79.84 55.88,79.84 55.24,79.21 49.53,79.21 OUT7-8.13
N$115
  Top 0.254: IC8.15 66.67,83.02 66.67,83.66 62.23,88.1 48.26,88.1 48.26,85.56 47.62,84.92 47.62,78.58 48.89,77.3 OUT7-8.11
N$116  (via drill 0.61)
  Top 0.254: v50.16,84.92 50.16,76.03 48.89,74.77 OUT7-8.9
  Bottom 0.254: v50.16,84.92 50.8,84.29 52.07,84.29 52.7,84.92 67.94,84.92 67.94,80.48 68.57,79.84 72.38,79.84 73.66,81.11 IC8.12
N$117
  Top 0.254: IC8.2 55.88,74.77 54.61,76.03 52.7,76.03 52.7,74.13 51.43,72.86 46.35,72.86 46.35,73.5 OUT7-8.10
N$118  (via drill 0.61)
  Top 0.254: v52.07,85.56 52.07,84.92 60.96,84.92 62.86,83.02 62.86,80.48 63.5,79.84 63.5,76.03 64.13,75.4 IC8.5 | v46.98,85.56 45.08,83.66 45.08,78.58 46.35,77.3 OUT7-8.12
  Bottom 0.254: v52.07,85.56 51.43,86.19 47.62,86.19 v46.98,85.56
N$119  (via drill 0.61)
  Top 0.254: v65.4,83.66 65.4,76.67 66.67,75.4 IC8.6
  Bottom 0.254: v65.4,83.66 46.35,83.66 45.08,82.39 45.08,79.84 46.35,79.84 OUT7-8.14
N$120  (via drill 0.61)
  Top 0.254: v73.66,79.21 73.66,76.03 74.29,75.4 IC8.9
  Bottom 0.254: v73.66,79.21 56.51,79.21 55.24,77.94 48.26,77.94 47.62,78.58 47.62,81.11 46.35,81.11 OUT7-8.16
N$121  (via drill 0.61)
  Top 0.254: v48.89,62.06 47.62,63.34 47.62,69.69 46.35,70.95 OUT7-8.8
  Bottom 0.254: v48.89,62.06 51.43,62.06 53.34,63.97 60.32,63.97 60.96,63.34 72.38,63.34 73.66,62.06 IC7.9
N$122  (via drill 0.61)
  Top 0.254: v66.67,57.62 66.67,60.16 IC7.6 | v43.81,57.62 v43.81,65.88
  Bottom 0.254: v66.67,57.62 66.03,56.98 44.45,56.98 v43.81,57.62 | v43.81,65.88 46.35,68.41 OUT7-8.6
N$123  (via drill 0.61)
  Top 0.254: v61.59,65.24 64.13,62.7 IC7.5
  Bottom 0.254: v61.59,65.24 60.96,65.88 50.16,65.88 49.53,65.24 48.26,65.24 46.98,66.51 OUT7-8.4
N$124
  Bottom 0.254: IC18.7 69.21,19.52 69.21,20.79 71.75,23.33 81.27,23.33 IN7-8.14
N$125  (via drill 0.61)
  Top 0.254: v71.75,22.06 71.75,24.6 IC18.13 | v83.18,22.06 83.18,20.15 84.45,18.88 IN7-8.9
  Bottom 0.254: v71.75,22.06 72.38,22.7 80.64,22.7 81.27,22.06 v83.18,22.06
N$126  (via drill 0.61)
  Top 0.254: v70.48,30.31 70.48,28.41 69.21,27.14 IC18.14 | v81.91,30.31 85.72,26.5 85.72,22.7 84.45,21.42 IN7-8.11
  Bottom 0.254: v70.48,30.31 v81.91,30.31
N$127
  Bottom 0.254: IC18.17 62.23,26.5 63.5,27.77 86.99,27.77 88.89,29.68 90.8,29.68 91.44,30.31 92.7,30.31 93.34,29.68 93.34,24.6 86.35,24.6 85.08,23.33 IN7-8.13
N$128  (via drill 0.61)
  Top 0.254: v80.64,29.04 83.81,25.87 IN7-8.15
  Bottom 0.254: v80.64,29.04 62.23,29.04 59.69,26.5 IC18.18
N$129
  Bottom 0.254: IC17.3 59.69,4.92 60.96,3.64 67.3,3.64 67.94,4.28 67.94,7.46 69.84,7.46 70.48,6.82 71.75,8.09 81.27,8.09 IN7-8.2
N$130  (via drill 0.61)
  Top 0.254: v61.59,8.73 61.59,6.82 IC17.4 | v70.48,8.09 v70.48,15.08
  Bottom 0.254: v61.59,8.73 62.23,8.09 v70.48,8.09 | v70.48,15.08 80.64,15.08 81.27,14.44 85.08,14.44 85.72,13.81 85.72,11.9 83.81,11.9 82.55,10.63 IN7-8.4
N$131  (via drill 0.61)
  Top 0.254: v81.27,3.64 83.18,5.55 83.18,11.27 81.91,12.54 IN7-8.6
  Bottom 0.254: v81.27,3.64 71.11,3.64 69.84,4.92 IC17.7
N$132
  Top 0.254: IC17.8 72.38,4.92 73.66,3.64 80,3.64 80,10 80.64,10.63 80.64,13.81 81.91,15.08 IN7-8.8
N$133  (via drill 0.61)
  Top 0.254: v74.29,9.36 71.75,11.9 IC17.13
  Bottom 0.254: v74.29,9.36 82.55,9.36 83.81,8.09 IN7-8.1
N$134
  Top 0.254: IC17.14 69.21,11.9 69.21,8.09 70.48,6.82 70.48,4.28 72.38,2.38 85.72,2.38 85.72,8.73 84.45,10 IN7-8.3
N$135
  Bottom 0.254: IC17.17 62.23,12.54 63.5,11.27 78.73,11.27 79.37,11.9 82.55,11.9 83.81,13.17 IN7-8.5
N$136
  Top 0.254: IC17.18 59.69,12.54 62.86,9.36 62.86,4.28 65.4,1.74 86.35,1.74 86.35,13.17 84.45,15.08 IN7-8.7
OUT00  (via drill 0.61)
  Top 0.254: v60.32,20.79 v60.32,34.76 | v86.35,35.39 88.26,37.3 88.26,39.2 87.62,39.84 87.62,64.61 v88.26,65.24 | v66.67,64.61 65.4,63.34 65.4,56.98 66.67,55.71 66.67,55.08 IC10.15
  Bottom 0.254: v60.32,20.79 53.97,20.79 50.16,16.98 37.46,16.98 36.83,16.34 IC1.11 | v60.32,34.76 60.32,37.94 83.81,37.94 v86.35,35.39 | v88.26,65.24 87.62,64.61 v66.67,64.61
OUT01  (via drill 0.61)
  Top 0.254: v61.59,31.58 62.86,32.85 62.86,42.38 65.4,44.92 65.4,47.46 69.21,51.27 73.02,51.27 73.02,55.08 72.38,55.71 69.21,55.71 69.21,55.08 IC10.14
  Bottom 0.254: v61.59,31.58 46.35,31.58 44.45,29.68 37.46,29.68 36.83,29.04 IC2.11
OUT02  (via drill 0.61)
  Top 0.254: v37.46,48.09 37.46,43.65 36.19,42.38 IC3.11 | v53.34,50 53.97,50.63 53.97,54.45 55.24,55.71 65.4,55.71 65.4,52.54 66.03,51.91 71.11,51.91 71.11,53.17 IC10.13
  Bottom 0.254: v37.46,48.09 39.37,50 v53.34,50
OUT03
  Bottom 0.254: IC4.11 36.83,54.45 38.1,55.71 72.38,55.71 73.66,54.45 IC10.12
OUT04  (via drill 0.61)
  Top 0.254: v41.27,69.05 43.18,70.95 v43.18,86.83 | v71.11,87.47 75.56,83.02 75.56,56.98 76.83,55.71 76.83,55.08 IC10.11
  Bottom 0.254: v41.27,69.05 38.73,69.05 36.83,67.14 IC5.11 | v43.18,86.83 44.45,88.1 70.48,88.1 v71.11,87.47
OUT05  (via drill 0.61)
  Top 0.254: v74.29,86.83 78.73,82.39 78.73,55.71 79.37,55.08 IC10.10 | v59.05,86.83 53.34,86.83 v53.34,86.19
  Bottom 0.254: v74.29,86.83 73.66,86.19 59.69,86.19 v59.05,86.83 | v53.34,86.19 52.7,86.83 45.72,86.83 44.45,85.56 41.27,85.56 40,84.29 40,81.75 41.27,80.48 41.27,79.21 36.83,79.21 IC6.11
OUT06  (via drill 0.61)
  Top 0.254: v80,65.88 80,56.98 81.91,55.08 IC10.9
  Bottom 0.254: v80,65.88 77.46,68.41 IC7.11
OUT07
  Top 0.254: IC10.7 79.37,47.46 78.1,48.73 78.1,79.21 76.83,80.48 IC8.11
PIA-A0  (via drill 0.61)
  Top 0.254: IC11.2 94.61,9.36 95.88,10.63 95.88,16.98 94.61,18.25 94.61,19.52 IC12.2 94.61,22.06 95.88,23.33 95.88,30.95 | 95.88,30.95 94.61,32.22 IC13.2 | 95.88,43.65 94.61,44.92 IC14.2 | 95.88,43.65 95.88,30.95 | 95.88,56.35 94.61,57.62 IC15.2 | 95.88,56.35 95.88,43.65 | 95.88,56.35 95.88,69.05 94.61,70.32 IC16.2 94.61,72.86 95.88,74.13 v95.88,81.11 | IC18.2 56.51,16.98 55.24,15.71 55.24,9.36 56.51,8.09 56.51,6.82 IC17.2 | IC7.3 59.05,62.7 57.78,63.97 57.78,70.95 59.05,72.22 59.05,72.86 IC8.3 | IC6.3 18.41,70.32 18.41,69.05 19.68,67.78 19.68,61.43 18.41,60.16 IC5.3 18.41,57.62 19.04,56.98 19.04,55.71 19.68,55.08 19.68,51.27 18.41,50 18.41,47.46 IC4.3 18.41,44.92 19.68,43.65 19.68,36.03 18.41,34.76 IC3.3 18.41,32.22 19.68,30.95 19.68,27.14 19.04,26.5 19.04,22.7 18.41,22.06 IC2.3 18.41,19.52 18.41,18.25 19.68,16.98 19.68,10.63 18.41,9.36 IC1.3
  Bottom 0.254: IC17.2 55.88,4.92 54.61,3.64 48.89,3.64 46.98,5.55 CORE-IO.1 45.72,5.55 44.45,4.28 41.91,4.28 41.27,4.92 21.58,4.92 19.04,7.46 IC1.3 | 57.78,75.4 57.15,76.03 52.7,76.03 52.07,75.4 31.11,75.4 29.2,73.5 20.31,73.5 19.04,72.22 IC6.3 | 57.78,75.4 58.41,74.77 IC8.3 | v95.88,81.11 86.35,81.11 83.18,77.94 62.86,77.94 62.23,78.58 60.96,78.58 57.78,75.4
PIA-A1  (via drill 0.61)
  Top 0.254: IC16.5 102.23,70.32 102.23,69.05 103.5,67.78 103.5,65.24 102.86,64.61 102.86,60.8 102.23,60.16 IC15.5 102.23,57.62 102.86,56.98 102.86,55.71 103.5,55.08 103.5,52.54 102.23,51.27 102.23,47.46 IC14.5 102.23,44.92 102.23,43.65 103.5,42.38 103.5,39.84 102.86,39.2 102.86,35.39 102.23,34.76 IC13.5 102.23,32.22 102.23,30.95 103.5,29.68 103.5,27.14 102.86,26.5 102.86,22.7 102.23,22.06 IC12.5 102.23,19.52 102.23,18.25 103.5,16.98 103.5,10.63 102.23,9.36 IC11.5 | IC17.5 64.13,6.82 65.4,8.09 65.4,14.44 64.13,15.71 64.13,16.98 IC18.5 | 60.32,66.51 60.32,70.32 61.59,71.59 61.59,72.86 IC8.4 | 60.32,66.51 60.32,63.97 61.59,62.7 IC7.4 | 22.22,18.25 22.22,10.63 20.95,9.36 IC1.4 | 22.22,18.25 20.95,19.52 IC2.4 | 22.22,30.95 20.95,32.22 IC3.4 | 22.22,18.25 22.22,30.95 | 22.22,43.65 20.95,44.92 IC4.4 | 22.22,30.95 22.22,43.65 | 22.22,56.35 20.95,57.62 IC5.4 | 22.22,43.65 22.22,56.35 | 22.22,56.35 22.22,69.05 20.95,70.32 IC6.4 | v67.94,57.62 67.94,64.61 66.03,66.51 60.32,66.51
  Bottom 0.254: IC1.4 21.58,7.46 23.49,5.55 43.18,5.55 CORE-IO.2 44.45,5.55 45.72,6.82 52.07,6.82 52.7,7.46 62.23,7.46 63.5,6.18 IC17.5 | IC7.4 60.96,62.06 59.69,63.34 58.41,63.34 57.78,62.7 57.78,58.25 46.98,58.25 44.45,60.8 22.86,60.8 21.58,59.52 IC5.4 | v67.94,57.62 68.57,58.25 69.21,58.25 69.84,57.62 90.8,57.62 90.8,60.16 91.44,60.8 100.32,60.8 101.59,59.52 IC15.5
PIA-A2  (via drill 0.61)
  Top 0.254: 106.04,18.25 106.04,10.63 104.77,9.36 IC11.6 | 106.04,18.25 104.77,19.52 IC12.6 | 106.04,30.95 104.77,32.22 IC13.6 | 106.04,30.95 106.04,18.25 | 106.04,43.65 104.77,44.92 IC14.6 | 106.04,43.65 106.04,30.95 | 106.04,56.35 104.77,57.62 IC15.6 | 106.04,56.35 106.04,43.65 | 106.04,56.35 v106.04,68.41 106.04,69.05 104.77,70.32 IC16.6 | 67.94,9.36 67.94,15.71 66.67,16.98 IC18.6 | 67.94,9.36 67.94,8.09 66.67,6.82 IC17.6 | IC1.7 28.57,9.36 29.2,10 29.2,13.81 29.84,14.44 29.84,16.98 28.57,18.25 28.57,19.52 IC2.7 28.57,22.06 29.2,22.7 29.2,26.5 29.84,27.14 29.84,29.68 28.57,30.95 28.57,32.22 IC3.7 28.57,34.76 29.84,36.03 29.84,42.38 28.57,43.65 28.57,44.92 IC4.7 28.57,47.46 29.84,48.73 29.84,55.08 28.57,56.35 28.57,57.62 IC5.7 28.57,60.16 29.84,61.43 29.84,67.78 28.57,69.05 28.57,70.32 IC6.7 | v66.67,9.36 67.94,9.36 | IC8.7 69.21,72.86 67.94,71.59 67.94,67.78 68.57,67.14 68.57,63.34 69.21,62.7 IC7.7 69.21,60.16 v69.21,56.98
  Bottom 0.254: IC1.7 29.2,7.46 30.47,6.18 36.83,6.18 37.46,6.82 44.45,6.82 45.72,8.09 CORE-IO.3 46.98,8.09 48.89,10 66.03,10 v66.67,9.36 | v69.21,56.98 68.57,56.35 31.11,56.35 29.2,58.25 IC5.7 | v106.04,68.41 105.41,69.05 85.08,69.05 81.91,72.22 71.11,72.22 69.84,73.5 IC8.7
PIA-A3  (via drill 0.61)
  Top 0.254: 32.38,18.25 32.38,10.63 31.11,9.36 IC1.8 | 32.38,18.25 31.11,19.52 IC2.8 | 32.38,30.95 31.11,32.22 IC3.8 | 32.38,18.25 32.38,30.95 | 32.38,43.65 31.11,44.92 IC4.8 | 32.38,30.95 32.38,43.65 | 32.38,56.35 31.11,57.62 IC5.8 | 32.38,43.65 32.38,51.91 | 32.38,51.91 32.38,56.35 | 32.38,56.35 32.38,69.05 31.11,70.32 IC6.8 | IC11.9 112.39,9.36 113.02,10 113.02,13.81 113.66,14.44 113.66,16.98 112.39,18.25 112.39,19.52 IC12.9 112.39,22.06 112.39,24.6 113.66,25.87 113.66,30.95 112.39,32.22 IC13.9 112.39,34.76 113.02,35.39 113.02,39.2 113.66,39.84 113.66,42.38 112.39,43.65 112.39,44.92 IC14.9 112.39,47.46 113.02,48.09 113.02,51.91 113.66,52.54 113.66,55.08 112.39,56.35 112.39,57.62 IC15.9 112.39,60.16 112.39,63.97 113.66,65.24 113.66,67.78 113.02,68.41 113.02,69.69 112.39,70.32 IC16.9 | IC8.8 71.75,72.86 71.75,71.59 70.48,70.32 70.48,63.97 71.75,62.7 IC7.8 71.75,60.16 74.92,56.98 74.92,55.71 75.56,55.08 v75.56,51.27 75.56,20.79 74.29,19.52 IC18.9 74.29,16.98 74.29,15.71 75.56,14.44 75.56,8.09 74.29,6.82 IC17.9 | 32.38,51.91 38.73,51.91 v38.73,52.54
  Bottom 0.254: CORE-IO.4 43.18,8.09 41.27,10 33.02,10 31.74,8.73 IC1.8 | IC14.9 111.75,45.55 110.48,44.28 99.05,44.28 98.42,44.92 98.42,50.63 76.19,50.63 v75.56,51.27 62.86,51.27 62.86,54.45 62.23,55.08 41.27,55.08 v38.73,52.54
PIA-A4  (via drill 0.61)
  Top 0.254: IC6.13 31.11,77.94 29.84,76.67 29.84,69.05 31.11,67.78 IC5.13 31.11,65.24 31.11,61.43 29.84,60.16 29.84,56.35 31.11,55.08 IC4.13 31.11,52.54 31.11,48.73 29.84,47.46 29.84,43.65 31.11,42.38 IC3.13 31.11,39.84 30.47,39.2 30.47,35.39 29.84,34.76 29.84,30.95 31.11,29.68 IC2.13 31.11,27.14 29.84,25.87 29.84,18.25 31.11,16.98 IC1.13 31.11,14.44 29.84,13.17 29.84,2.38 42.54,2.38 45.08,4.92 45.08,8.73 46.35,10 CORE-IO.5 | IC7.13 71.75,70.32 73.02,71.59 73.02,78.58 71.75,79.84 71.75,80.48 IC8.13 | 73.02,20.79 73.02,23.33 74.29,24.6 IC18.12 | 73.02,20.79 73.02,15.71 74.29,14.44 IC17.12 | 111.12,25.87 111.12,18.25 112.39,16.98 IC11.12 | 111.12,25.87 112.39,27.14 IC12.12 | 111.12,38.57 112.39,39.84 IC13.12 | 111.12,25.87 111.12,38.57 | 111.12,51.27 112.39,52.54 IC14.12 | 111.12,38.57 111.12,51.27 | v74.29,20.79 73.02,20.79 | 111.12,51.27 111.12,60.16 111.75,60.8 111.75,64.61 112.39,65.24 IC15.12 112.39,67.78 111.12,69.05 111.12,76.03 112.39,77.3 112.39,77.94 IC16.12 112.39,80.48 v112.39,86.19 | v79.37,10.63 v79.37,20.15
  Bottom 0.254: v74.29,20.79 74.92,20.15 v79.37,20.15 80.64,20.15 81.27,19.52 90.8,19.52 92.7,17.61 110.48,17.61 111.75,16.34 IC11.12 | v112.39,86.19 111.75,85.56 75.56,85.56 72.38,82.39 IC8.13 | v79.37,10.63 46.98,10.63 CORE-IO.5
PIA-A5  (via drill 0.61)
  Top 0.254: IC7.14 69.21,70.32 70.48,71.59 70.48,79.21 69.21,80.48 IC8.14 | IC11.15 104.77,16.98 103.5,18.25 103.5,25.87 104.77,27.14 IC12.15 104.77,29.68 103.5,30.95 103.5,38.57 104.77,39.84 IC13.15 104.77,42.38 103.5,43.65 103.5,51.27 104.77,52.54 IC14.15 104.77,55.08 103.5,56.35 103.5,63.97 104.77,65.24 IC15.15 104.77,67.78 103.5,69.05 103.5,76.67 104.77,77.94 IC16.15 | IC17.15 66.67,14.44 65.4,15.71 65.4,22.06 66.67,23.33 66.67,24.6 IC18.15 | 27.3,25.87 27.3,18.25 28.57,16.98 IC1.14 28.57,14.44 28.57,13.17 v27.93,12.54 | 27.3,25.87 28.57,27.14 IC2.14 | 27.3,38.57 28.57,39.84 IC3.14 | 27.3,25.87 27.3,38.57 | 27.3,51.27 28.57,52.54 IC4.14 | 27.3,38.57 27.3,51.27 | 27.3,51.27 27.3,63.97 28.57,65.24 IC5.14 28.57,67.78 27.3,69.05 27.3,76.67 28.57,77.94 IC6.14
  Bottom 0.254: IC15.15 104.13,67.14 102.86,68.41 84.45,68.41 81.91,70.95 71.11,70.95 69.84,69.69 IC7.14 68.57,69.69 67.3,70.95 50.16,70.95 49.53,70.32 37.46,70.32 35.55,68.41 30.47,68.41 29.2,67.14 IC5.14 | v27.93,12.54 41.27,12.54 43.18,10.63 CORE-IO.6 | IC18.15 66.03,25.23 64.77,23.96 47.62,23.96 46.98,24.6 32.38,24.6 29.2,27.77 IC2.14
PIA-A6  (via drill 0.61)
  Top 0.254: 62.86,77.3 62.86,79.21 61.59,80.48 IC8.17 60.96,82.39 59.05,84.29 51.43,84.29 51.43,84.92 50.16,86.19 48.89,86.19 v48.89,84.92 | 62.86,77.3 62.86,71.59 61.59,70.32 IC7.17 | IC11.16 102.23,16.98 100.96,18.25 100.96,22.06 102.23,23.33 102.23,27.14 IC12.16 102.23,29.68 100.96,30.95 100.96,38.57 | 100.96,38.57 102.23,39.84 IC13.16 | 100.96,51.27 102.23,52.54 IC14.16 | 100.96,51.27 100.96,38.57 | 100.96,63.97 102.23,65.24 IC15.16 | 100.96,63.97 100.96,51.27 | 100.96,63.97 100.96,76.67 102.23,77.94 IC16.16 | 62.86,77.3 v62.23,77.3 | IC17.16 64.13,14.44 62.86,15.71 62.86,23.33 64.13,24.6 IC18.16 | IC1.17 20.95,16.98 19.68,18.25 19.68,25.87 20.95,27.14 IC2.17 20.95,29.68 20.95,30.95 19.68,32.22 19.68,34.76 20.31,35.39 20.31,39.2 20.95,39.84 IC3.17 20.95,42.38 20.31,43.02 20.31,44.28 19.68,44.92 19.68,50 20.95,51.27 20.95,52.54 IC4.17 20.95,55.08 19.68,56.35 19.68,60.16 20.95,61.43 20.95,65.24 IC5.17 20.95,67.78 19.68,69.05 19.68,76.67 20.95,77.94 IC6.17 20.95,80.48 20.95,86.83 27.3,86.83 29.84,84.29 v41.27,84.29
  Bottom 0.254: v62.23,77.3 86.35,77.3 86.99,77.94 90.8,77.94 91.44,77.3 100.32,77.3 101.59,78.58 IC16.16 | IC17.16 63.5,13.81 62.23,15.08 53.34,15.08 52.7,14.44 48.26,14.44 46.98,13.17 CORE-IO.7 45.72,13.17 44.45,14.44 37.46,14.44 36.83,13.81 35.55,13.81 34.92,14.44 34.92,17.61 22.86,17.61 21.58,16.34 IC1.17 | v48.89,84.92 48.26,84.29 v41.27,84.29
PIA-A7  (via drill 0.61)
  Top 0.254: IC8.18 59.05,80.48 60.32,79.21 60.32,71.59 59.05,70.32 IC7.18 59.05,67.78 59.69,67.14 59.69,63.34 60.32,62.7 v60.32,59.52 | 93.34,25.87 93.34,18.25 94.61,16.98 IC11.19 | 93.34,25.87 94.61,27.14 IC12.19 | 93.34,38.57 94.61,39.84 IC13.19 | 93.34,38.57 93.34,25.87 | 93.34,51.27 94.61,52.54 IC14.19 | 93.34,38.57 93.34,51.27 | 93.34,63.97 94.61,65.24 IC15.19 | 93.34,51.27 93.34,63.97 | 93.34,63.97 93.34,76.67 94.61,77.94 IC16.19 | 17.14,18.25 18.41,16.98 IC1.18 | 17.14,18.25 17.14,25.87 | 17.14,25.87 18.41,27.14 IC2.18 | 17.14,38.57 18.41,39.84 IC3.18 | 17.14,25.87 17.14,38.57 | 17.14,51.27 18.41,52.54 IC4.18 | 17.14,38.57 17.14,51.27 | 17.14,63.97 18.41,65.24 IC5.18 | 17.14,51.27 17.14,63.97 | 17.14,63.97 17.14,76.67 18.41,77.94 IC6.18 | 17.14,18.25 17.14,1.74 56.51,1.74 57.78,3.01 57.78,10.63 56.51,11.9 IC17.19 56.51,14.44 57.78,15.71 57.78,23.33 56.51,24.6 IC18.19 56.51,27.14 59.05,29.68 59.05,48.73 v60.32,50
  Bottom 0.254: v60.32,59.52 74.92,59.52 75.56,60.16 75.56,63.97 92.07,63.97 93.97,65.88 IC15.19 | CORE-IO.8 44.45,13.17 45.72,11.9 52.7,11.9 53.34,11.27 54.61,11.27 55.88,12.54 IC17.19 | v60.32,50 95.88,50 95.88,44.92 95.24,44.28 94.61,44.28 94.61,42.38 IC13.19
PIA-B0  (via drill 0.61)
  Top 0.254: v44.45,30.95 42.54,29.04 42.54,25.23 43.18,24.6 44.45,24.6 45.08,23.96 45.08,22.7 46.35,21.42 CORE-IO.13
  Bottom 0.254: 60.32,33.49 63.5,33.49 IC9.1 | 60.32,33.49 59.05,34.76 59.05,39.2 67.3,39.2 67.94,39.84 67.94,44.28 66.03,44.28 64.77,45.55 IC10.1 | v44.45,30.95 45.72,32.22 59.05,32.22 60.32,33.49
PIA-B1  (via drill 0.61)
  Top 0.254: 65.4,36.03 66.67,34.76 IC9.2 | 65.4,36.03 65.4,43.65 66.67,44.92 IC10.2 | v64.13,22.06 65.4,23.33 65.4,36.03
  Bottom 0.254: v64.13,22.06 63.5,22.7 48.89,22.7 48.26,22.06 45.72,22.06 44.45,20.79 CORE-IO.14
PIA-B2  (via drill 0.61)
  Top 0.254: 67.94,36.03 69.21,34.76 IC9.3 | 67.94,36.03 67.94,43.65 69.21,44.92 IC10.3 | v67.94,23.33 67.94,36.03
  Bottom 0.254: v67.94,23.33 46.98,23.33 CORE-IO.15
PIA-B3
  Top 0.254: IC19.1 43.18,50.63 41.91,49.37 41.91,24.6 43.18,23.33 CORE-IO.16
PIA-B4  (via drill 0.61)
  Top 0.254: v39.37,28.41 39.37,47.46 41.27,49.37 41.27,52.54 45.08,52.54 45.72,51.91 45.72,50.63 44.45,49.37 IC19.2
  Bottom 0.254: v39.37,28.41 40.64,27.14 44.45,27.14 45.72,25.87 CORE-IO.17
PIA-B5
  Top 0.254: IC19.3 44.45,45.55 45.72,44.28 45.72,29.68 45.08,29.04 45.08,27.77 43.81,26.5 CORE-IO.18
PIA-B6  (via drill 0.61)
  Top 0.254: v83.81,35.39 84.45,36.03 v84.45,39.84 | v48.89,21.42 48.89,28.41 46.98,28.41 CORE-IO.19 | v69.21,23.33 70.48,24.6 70.48,27.14 71.75,28.41 71.75,32.22 IC9.4
  Bottom 0.254: v83.81,35.39 73.66,35.39 72.38,34.12 IC9.4 | v84.45,39.84 87.62,43.02 91.44,43.02 93.34,44.92 93.34,48.09 90.8,48.09 86.99,44.28 78.73,44.28 77.46,45.55 IC10.6 | v48.89,21.42 49.53,22.06 62.86,22.06 64.13,20.79 66.67,20.79 v69.21,23.33
PIA-B7  (via drill 0.61)
  Top 0.254: v50.8,29.68 54.61,33.49 JP1.17
  Bottom 0.254: IC19.5 45.08,41.11 48.89,37.3 55.88,37.3 56.51,36.66 56.51,34.12 55.24,34.12 JP1.17 | v50.8,29.68 45.72,29.68 44.45,28.41 CORE-IO.20
VCC  (via drill 0.61)
  Top 0.508: BYP5.1 10.79,67.14 10.79,72.22 13.33,74.77 13.33,77.94 IC6.20 | 14.6,25.87 14.6,18.25 13.33,16.98 IC1.20 | 14.6,25.87 13.33,27.14 IC2.20 | 14.6,38.57 13.33,39.84 IC3.20 | 14.6,25.87 14.6,38.57 | 14.6,38.57 14.6,43.65 | 14.6,43.65 14.6,51.27 13.33,52.54 IC4.20 | IC5.20 13.33,65.24 13.33,63.97 12.7,63.34 12.7,61.43 10.79,59.52 10.79,54.45 BYP4.1 | 52.7,13.17 52.07,13.17 BYP18.1 | 52.7,13.17 53.34,13.17 IC17.20 | 62.86,53.81 63.5,53.81 IC10.16 | 62.86,53.81 62.23,53.81 BYP10.1 | IC19.16 50.8,51.91 50.16,52.54 50.16,53.17 BYP17.1 | BYP7.1 51.43,68.41 50.16,67.14 50.16,54.45 BYP17.1 | 62.86,53.81 62.86,44.92 62.23,44.28 62.23,42.38 61.59,41.74 BYP9.1 | BYP19.1 51.43,26.5 49.53,28.41 49.53,53.81 BYP17.1 | 14.6,43.65 v15.87,43.65 | IC11.11 114.93,16.98 113.66,18.25 113.66,24.6 114.93,25.87 114.93,27.14 IC12.11 114.93,29.68 114.3,30.31 114.3,31.58 113.66,32.22 113.66,38.57 114.93,39.84 IC13.11 114.93,42.38 113.66,43.65 113.66,51.27 114.93,52.54 IC14.11 114.93,55.08 113.66,56.35 113.66,63.97 114.93,65.24 IC15.11 114.93,67.78 113.66,69.05 113.66,76.67 114.93,77.94 IC16.11 114.93,80.48 113.66,81.75 v113.66,85.56 | BYP8.1 52.07,81.75 53.34,81.75 IC8.20 53.97,80.48 57.78,76.67 v57.78,72.22 | v80,76.03 79.37,76.67 79.37,80.48 80.64,81.75 JP2.2 82.55,82.39 82.55,87.47 83.18,88.1 89.53,88.1 89.53,79.84 BYP16.1 90.16,79.21 91.44,79.21 IC16.20 92.07,77.94 90.8,76.67 90.8,66.51 | BYP11.1 90.16,15.71 91.44,15.71 IC11.20 92.07,16.98 90.8,18.25 90.8,25.87 89.53,27.14 89.53,27.77 BYP12.1 89.53,29.04 89.53,31.58 90.8,32.85 90.8,41.11 | IC17.11 76.83,14.44 75.56,15.71 75.56,19.52 76.83,20.79 76.83,24.6 IC18.11 76.83,27.14 76.83,32.22 IC9.6
  Top 0.508: 90.8,66.51 91.44,66.51 IC15.20 92.07,65.24 90.8,63.97 90.8,53.81 | 90.8,66.51 90.16,66.51 BYP15.1 | 90.8,41.11 91.44,41.11 IC13.20 92.07,42.38 90.8,43.65 90.8,53.81 | 90.8,41.11 90.16,41.11 BYP13.1 | 90.8,53.81 91.44,53.81 IC14.20 | 90.8,53.81 90.16,53.81 BYP14.1 89.53,54.45 v89.53,58.89 | v38.1,42.38 38.73,43.02 38.73,48.73 40.64,50.63 40.64,53.17 v41.27,53.81 | v52.07,53.81 56.51,58.25 v64.13,58.25 | CORE-IO.12 43.81,17.61 42.54,16.34 42.54,15.08 43.18,14.44 45.72,14.44 45.72,15.71 CORE-IO.9 | IC18.20 53.34,25.87 52.07,25.87 BYP19.1 | BYP19.1 52.7,24.6 v52.7,15.71 52.7,13.17
  Bottom 0.508: BYP5.1 11.43,66.51 12.7,66.51 IC5.20 | BYP6.1 11.43,79.21 12.7,79.21 IC6.20 | BYP4.1 11.43,53.81 12.7,53.81 IC4.20 | BYP3.1 11.43,41.11 12.7,41.11 IC3.20 | BYP1.1 11.43,15.71 12.7,15.71 IC1.20 | BYP2.1 11.43,28.41 12.7,28.41 IC2.20 | 41.91,42.38 41.91,40.48 43.18,39.2 IC19.6 42.54,38.57 38.73,42.38 v38.1,42.38 | 61.59,42.38 64.13,42.38 IC9.16 | 41.91,42.38 61.59,42.38 | 61.59,42.38 61.59,41.74 BYP9.1 | BYP7.1 52.07,69.05 53.34,69.05 IC7.20 | BYP10.1 60.96,53.81 59.69,52.54 53.97,52.54 52.7,51.27 IC19.16 | v15.87,43.65 16.5,43.02 38.73,43.02 39.37,42.38 41.91,42.38 | v57.78,72.22 67.3,72.22 67.94,72.86 67.94,76.03 v80,76.03 | IC12.20 91.44,28.41 90.16,28.41 BYP12.1 88.89,28.41 87.62,27.14 76.83,27.14 IC18.11 | v89.53,58.89 82.55,58.89 BYP20.1 81.27,58.89 64.77,58.89 v64.13,58.25 | v113.66,85.56 113.02,84.92 86.35,84.92 83.18,81.75 JP2.2 | v41.27,53.81 42.54,52.54 50.8,52.54 v52.07,53.81 | v52.7,15.71 46.98,15.71 CORE-IO.9

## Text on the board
Top: PA8PDP/VRS | Component Side
Bottom: Solder Side
tPlace: 16 | 16 | 16 | 1 | 1 | 1 | 1 | 16 | 16 | 1 | 1 | 18 | 16 | 20 | 16 | 16 | 1 | 1 | 1 | 1
tNames: BYP8 | BYP6 | BYP16 | JP2 | IC8 | IC6 | IC16 | BYP7 | BYP5 | BYP15 | OUT7-8 | IC7 | OUT5-6 | IN5-6 | IC5 | IC15 | BYP20 | JP1 | BYP4 | BYP10 | BYP14 | IC19 | BYP17 | IC10 | IC4 | IC14 | BYP3 | BYP9 | BYP13 | OUT3-4 | IC3 | IC9 | IC13 | IN3-4 | BYP2 | BYP12 | BYP19 | IC2 | IC12 | IC18 | BYP1 | BYP11 | BYP18 | OUT1-2 | IN1-2 | IC1 | IC11 | IC17 | IN7-8 | CORE-IO
tValues: RealConsole I/O - Rev.1 | + | .01uf | .01uf | .01uf | - | 74LS374N | POWER | 74LS374N | 74LS373N | - | .01uf | .01uf | .01uf | 74LS374N | 100uf 25V | 74LS374N | 74LS373N | + | .01uf | .01uf | .01uf | .01uf | 74LS374N | 74LS138N | 74LS138N | 74LS373N | .01uf | .01uf | .01uf | DEVSEL | 74LS374N | 74LS138N | 74LS373N | .01uf | .01uf | .01uf | 74LS374N | 74LS373N | 74LS373N | CORE-IO | .01uf | .01uf | .01uf | 74LS374N | 74LS373N | 74LS373N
